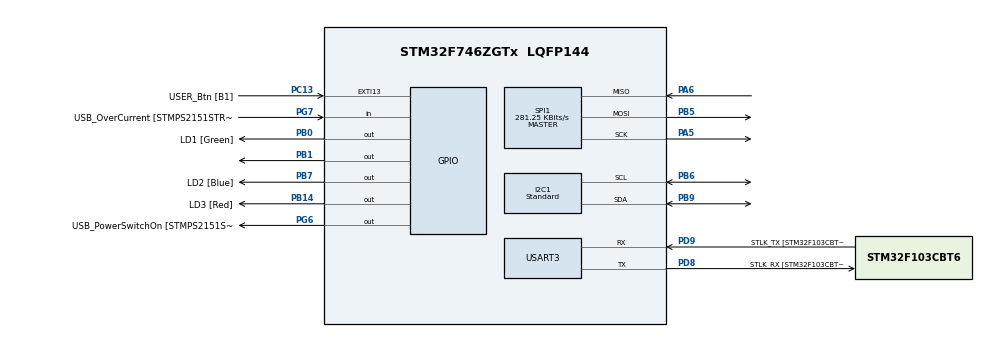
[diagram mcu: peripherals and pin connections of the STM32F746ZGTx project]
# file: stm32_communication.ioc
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FATFS._MAX_SS=1024
FATFS._MIN_SS=512
FREERTOS.Tasks01=defaultTask,24,128,StartDefaultTask,Default,NULL,Dynamic,NULL,NULL
FREERTOS.configUSE_NEWLIB_REENTRANT=1
I2C1.I2C_Speed_Mode=I2C_Standard
I2C1.Timing=0x00808CD2
Mcu.Family=STM32F7
Mcu.Name=STM32F746ZGTx
Mcu.Package=LQFP144
NVIC.I2C1_EV_IRQn=true\:5\:0\:false\:false\:true\:true\:true\:true\:true
NVIC.PriorityGroup=NVIC_PRIORITYGROUP_4
NVIC.SPI1_IRQn=true\:5\:0\:false\:false\:true\:true\:true\:true\:true
NVIC.TIM3_IRQn=true\:15\:0\:false\:false\:true\:false\:false\:true\:true
NVIC.TimeBase=TIM3_IRQn
NVIC.TimeBaseIP=TIM3
PA1.GPIO_Label=RMII_REF_CLK [LAN8742A-CZ-TR_REFCLK0]
PA1.Signal=ETH_REF_CLK
PA10.GPIO_Label=USB_ID
PA10.Signal=USB_OTG_FS_ID
PA11.GPIO_Label=USB_DM
PA11.Signal=USB_OTG_FS_DM
PA12.GPIO_Label=USB_DP
PA12.Signal=USB_OTG_FS_DP
PA13.GPIO_Label=TMS
PA13.Mode=Serial_Wire
PA13.Signal=SYS_JTMS-SWDIO
PA14.GPIO_Label=TCK
PA14.Mode=Serial_Wire
PA14.Signal=SYS_JTCK-SWCLK
PA2.GPIO_Label=RMII_MDIO [LAN8742A-CZ-TR_MDIO]
PA2.Signal=ETH_MDIO
PA5.Mode=Full_Duplex_Master
PA5.Signal=SPI1_SCK
PA6.Mode=Full_Duplex_Master
PA6.Signal=SPI1_MISO
PA7.GPIO_Label=RMII_CRS_DV [LAN8742A-CZ-TR_CRS_DV]
PA7.Signal=ETH_CRS_DV
PA8.GPIO_Label=USB_SOF [TP1]
PA8.Signal=USB_OTG_FS_SOF
PA9.GPIO_Label=USB_VBUS
PA9.Signal=USB_OTG_FS_VBUS
PB0.GPIO_Label=LD1 [Green]
PB0.Signal=GPIO_Output
PB1.Signal=GPIO_Output
PB13.GPIO_Label=RMII_TXD1 [LAN8742A-CZ-TR_TXD1]
PB13.Signal=ETH_TXD1
PB14.GPIO_Label=LD3 [Red]
PB14.Signal=GPIO_Output
PB3.GPIO_Label=SW0
PB3.Signal=SYS_JTDO-SWO
PB5.Mode=Full_Duplex_Master
PB5.Signal=SPI1_MOSI
PB6.GPIO_Pu=GPIO_PULLUP
PB6.Mode=I2C
PB6.Signal=I2C1_SCL
PB7.GPIO_Label=LD2 [Blue]
PB7.Signal=GPIO_Output
PB9.GPIO_Pu=GPIO_PULLUP
PB9.Mode=I2C
PB9.Signal=I2C1_SDA
PC1.GPIO_Label=RMII_MDC [LAN8742A-CZ-TR_MDC]
PC1.Signal=ETH_MDC
PC13.GPIO_Label=USER_Btn [B1]
PC13.Signal=GPXTI13
PC14/OSC32_IN.Mode=LSE-External-Oscillator
PC14/OSC32_IN.Signal=RCC_OSC32_IN
PC15/OSC32_OUT.Mode=LSE-External-Oscillator
PC15/OSC32_OUT.Signal=RCC_OSC32_OUT
PC4.GPIO_Label=RMII_RXD0 [LAN8742A-CZ-TR_RXD0]
PC4.Signal=ETH_RXD0
PC5.GPIO_Label=RMII_RXD1 [LAN8742A-CZ-TR_RXD1]
PC5.Signal=ETH_RXD1
PD8.GPIO_Label=STLK_RX [STM32F103CBT6_PA3]
PD8.Mode=Asynchronous
PD8.Signal=USART3_TX
PD9.GPIO_Label=STLK_TX [STM32F103CBT6_PA2]
PD9.Mode=Asynchronous
PD9.Signal=USART3_RX
PG11.GPIO_Label=RMII_TX_EN [LAN8742A-CZ-TR_TXEN]
PG11.Signal=ETH_TX_EN
PG13.GPIO_Label=RMII_TXD0 [LAN8742A-CZ-TR_TXD0]
PG13.Signal=ETH_TXD0
PG6.GPIO_Label=USB_PowerSwitchOn [STMPS2151STR_EN]
PG6.Signal=GPIO_Output
PG7.GPIO_Label=USB_OverCurrent [STMPS2151STR_FAULT]
PG7.Signal=GPIO_Input
PH0/OSC_IN.GPIO_Label=MCO [STM32F103CBT6_PA8]
PH0/OSC_IN.Mode=HSE-External-Clock-Source
PH0/OSC_IN.Signal=RCC_OSC_IN
PH1/OSC_OUT.Mode=HSE-External-Clock-Source
PH1/OSC_OUT.Signal=RCC_OSC_OUT
ProjectManager.HeapSize=0x200
ProjectManager.StackSize=0x400
ProjectManager.TargetToolchain=STM32CubeIDE
RCC.48MHZClocksFreq_Value=24000000
RCC.AHBFreq_Value=72000000
RCC.APB1CLKDivider=RCC_HCLK_DIV2
RCC.APB1Freq_Value=36000000
RCC.APB1TimFreq_Value=72000000
RCC.APB2Freq_Value=72000000
RCC.APB2TimFreq_Value=72000000
RCC.CortexFreq_Value=72000000
RCC.HCLKFreq_Value=72000000
RCC.HSE_VALUE=8000000
RCC.HSI_VALUE=16000000
RCC.PLLM=4
RCC.PLLMUL=RCC_PLL_MUL9
RCC.PLLN=72
RCC.PLLQ=3
RCC.PLLSourceVirtual=RCC_PLLSOURCE_HSE
RCC.PRESCALERUSB=RCC_USBCLKSOURCE_PLL_DIV1_5
RCC.SYSCLKFreq_VALUE=72000000
RCC.SYSCLKSource=RCC_SYSCLKSOURCE_PLLCLK
RCC.SYSCLKSourceVirtual=RCC_SYSCLKSOURCE_PLLCLK
RCC.USBFreq_Value=48000000
RCC.VCOOutputFreq_Value=144000000
SPI1.BaudRatePrescaler=SPI_BAUDRATEPRESCALER_256
SPI1.CalculateBaudRate=281.25 KBits/s
SPI1.DataSize=SPI_DATASIZE_8BIT
SPI1.Direction=SPI_DIRECTION_2LINES
SPI1.Mode=SPI_MODE_MASTER
SPI1.VirtualType=VM_MASTER
USART3.VirtualMode-Asynchronous=VM_ASYNC
VP_FATFS_VS_Generic.Mode=User_defined
VP_FREERTOS_VS_CMSIS_V2.Mode=CMSIS_V2
VP_SYS_VS_tim3.Mode=TIM3
board=NUCLEO-F746ZG

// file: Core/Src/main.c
/* USER CODE BEGIN Header */
/**
  ******************************************************************************
  * @file           : main.c
  * @brief          : Main program body
  ******************************************************************************
  * @attention
  *
  * Copyright (c) 2023 STMicroelectronics.
  * All rights reserved.
  *
  * This software is licensed under terms that can be found in the LICENSE file
  * in the root directory of this software component.
  * If no LICENSE file comes with this software, it is provided AS-IS.
  *
  ******************************************************************************
  */
/* USER CODE END Header */
#include "main.h"
#include "cmsis_os.h"
#include "fatfs.h"
#include "lwip.h"

/* USER CODE BEGIN Includes */
#include "lib/drivers/I2C/I2C.h"
#include "lib/drivers/SPI/SPI.h"
#include "lib/UL/HTU21D/HTU21D.h"
#include "lib/UL/LCD/display.h"
#include "string.h"
#include "lib/UL/SD/SD.h"
#include "FreeRTOS.h"
#include "queue.h"
#include "task.h"
//#include "message_buffer.h"
/* USER CODE END Includes */

/* USER CODE BEGIN PD */
#define SD_CS_GPIO_Port GPIOB
#define SD_CS_Pin GPIO_PIN_2
/* USER CODE END PD */

I2C_HandleTypeDef hi2c1;

SPI_HandleTypeDef hspi1;

UART_HandleTypeDef huart3;

/* Definitions for defaultTask */
osThreadId_t defaultTaskHandle;
const osThreadAttr_t defaultTask_attributes = {
  .name = "defaultTask",
  .stack_size = 128 * 4,
  .priority = (osPriority_t) osPriorityNormal,
};
/* USER CODE BEGIN PV */

/* Definitions for task */
xTaskHandle display_taskHandle;
xTaskHandle SD_taskHandle;
xTaskHandle HTU_taskHandle;
xTaskHandle ethernet_taskHandle;

i2c_t obj_i2c =
{
  .i2c_handler = &hi2c1,
  .i2c_type    = I2C1,
};

spi_t obj_spi =
{
  .obj_spi_handler = &hspi1,
  .obj_spi_type    = SPI1,
};

extern struct netif gnetif;
/* USER CODE END PV */

void SystemClock_Config(void);
static void MX_GPIO_Init(void);
static void MX_USART3_UART_Init(void);
static void MX_I2C1_Init(void);
static void MX_SPI1_Init(void);
void StartDefaultTask(void *argument);

/* USER CODE BEGIN PFP */
void display_task_entry(void *pvParameters);
void SD_task_entry(void *pvParameters);
void HTU_task_entry(void *pvParameters);
void ethernet_task_entry(void *pvParameters);
QueueHandle_t obj_display_que;

/* USER CODE END PFP */

/* USER CODE BEGIN 0 */

FATFS fs;  // file system
FIL fil; // File
FILINFO fno;
FRESULT fresult;  // result
UINT br, bw;  // File read/write count

/**** capacity related *****/
FATFS *pfs;
DWORD fre_clust;
uint32_t total, free_space;

#define BUFFER_SIZE 128
char buffer[BUFFER_SIZE];  // to store strings..

int i=0;

int bufsize (char *buf)
{
  int i = 0;
  while (*buf++ != '\0')
    i++;
  return i;
}

void clear_buffer (void)
{
  for (int i = 0; i < BUFFER_SIZE; i++)
    buffer[i] = '\0';
}

volatile uint8_t u8_fat_fs_cnt = 0;
volatile uint16_t u16_timer1, u16_timer2;

void SDTimer_Handler(void)
{
  if(u16_timer1 > 0)
    u16_timer1--;

  if(u16_timer2 > 0)
    u16_timer2--;
}

/* USER CODE END 0 */

int main(void)
{

  /* MCU Configuration--------------------------------------------------------*/

  /* Reset of all peripherals, Initializes the Flash interface and the Systick. */
  HAL_Init();

  /* Configure the system clock */
  SystemClock_Config();

  /* Initialize all configured peripherals */
  MX_GPIO_Init();
  MX_USART3_UART_Init();
  MX_I2C1_Init();
  MX_SPI1_Init();
  MX_FATFS_Init();
  /* USER CODE BEGIN 2 */

  i2c_init(&obj_i2c);
  SPI_init(&obj_spi);
//  display_write_test();
//_____________________________________

  HAL_Delay (500);

  /* USER CODE END 2 */

  /* Init scheduler */
  osKernelInitialize();

  /* USER CODE BEGIN RTOS_QUEUES */
  obj_display_que = xQueueCreate(200, sizeof(uint8_t));
  /* USER CODE END RTOS_QUEUES */

  /* Create the thread(s) */
  /* creation of defaultTask */
  defaultTaskHandle = osThreadNew(StartDefaultTask, NULL, &defaultTask_attributes);

  /* USER CODE BEGIN RTOS_THREADS */
  /* add threads, ... */
  xTaskCreate(display_task_entry, "display_task", 128 * 4, NULL, 32 | portPRIVILEGE_BIT, &display_taskHandle);
  xTaskCreate(SD_task_entry, "SD_task", 2 *128 * 4, NULL, 34 | portPRIVILEGE_BIT, &SD_taskHandle);
  xTaskCreate(HTU_task_entry, "HTU_task", 128 * 4, NULL, 33 | portPRIVILEGE_BIT, &HTU_taskHandle);
  xTaskCreate(ethernet_task_entry, "ethernet_task", 128 * 4, NULL, 31 | portPRIVILEGE_BIT, &ethernet_taskHandle);

  /* USER CODE END RTOS_THREADS */

  /* Start scheduler */
  osKernelStart();

  /* We should never get here as control is now taken by the scheduler */
  /* Infinite loop */
  /* USER CODE BEGIN WHILE */
  while (1)
  {

//    HTU21D_handler(&obj_i2c);
//    HAL_Delay(100);
      ethernetif_input(&gnetif);
      sys_check_timeouts();
//    display_run(&obj_i2c);
    /* USER CODE END WHILE */

  }
}

void SystemClock_Config(void)
{
  RCC_OscInitTypeDef RCC_OscInitStruct = {0};
  RCC_ClkInitTypeDef RCC_ClkInitStruct = {0};

  /** Configure LSE Drive Capability
  */
  HAL_PWR_EnableBkUpAccess();

  /** Configure the main internal regulator output voltage
  */
  __HAL_RCC_PWR_CLK_ENABLE();
  __HAL_PWR_VOLTAGESCALING_CONFIG(PWR_REGULATOR_VOLTAGE_SCALE1);

  /** Initializes the RCC Oscillators according to the specified parameters
  * in the RCC_OscInitTypeDef structure.
  */
  RCC_OscInitStruct.OscillatorType = RCC_OSCILLATORTYPE_HSE;
  RCC_OscInitStruct.HSEState = RCC_HSE_ON;
  RCC_OscInitStruct.PLL.PLLState = RCC_PLL_ON;
  RCC_OscInitStruct.PLL.PLLSource = RCC_PLLSOURCE_HSE;
  RCC_OscInitStruct.PLL.PLLM = 4;
  RCC_OscInitStruct.PLL.PLLN = 216;
  RCC_OscInitStruct.PLL.PLLP = RCC_PLLP_DIV2;
  RCC_OscInitStruct.PLL.PLLQ = 3;
  if (HAL_RCC_OscConfig(&RCC_OscInitStruct) != HAL_OK)
  {
    Error_Handler();
  }

  /** Activate the Over-Drive mode
  */
  if (HAL_PWREx_EnableOverDrive() != HAL_OK)
  {
    Error_Handler();
  }

  /** Initializes the CPU, AHB and APB buses clocks
  */
  RCC_ClkInitStruct.ClockType = RCC_CLOCKTYPE_HCLK|RCC_CLOCKTYPE_SYSCLK
                              |RCC_CLOCKTYPE_PCLK1|RCC_CLOCKTYPE_PCLK2;
  RCC_ClkInitStruct.SYSCLKSource = RCC_SYSCLKSOURCE_PLLCLK;
  RCC_ClkInitStruct.AHBCLKDivider = RCC_SYSCLK_DIV1;
  RCC_ClkInitStruct.APB1CLKDivider = RCC_HCLK_DIV4;
  RCC_ClkInitStruct.APB2CLKDivider = RCC_HCLK_DIV2;

  if (HAL_RCC_ClockConfig(&RCC_ClkInitStruct, FLASH_LATENCY_7) != HAL_OK)
  {
    Error_Handler();
  }
}

static void MX_I2C1_Init(void)
{

  hi2c1.Instance = I2C1;
  hi2c1.Init.Timing = 0x20404768;
  hi2c1.Init.OwnAddress1 = 0;
  hi2c1.Init.AddressingMode = I2C_ADDRESSINGMODE_7BIT;
  hi2c1.Init.DualAddressMode = I2C_DUALADDRESS_DISABLE;
  hi2c1.Init.OwnAddress2 = 0;
  hi2c1.Init.OwnAddress2Masks = I2C_OA2_NOMASK;
  hi2c1.Init.GeneralCallMode = I2C_GENERALCALL_DISABLE;
  hi2c1.Init.NoStretchMode = I2C_NOSTRETCH_DISABLE;
  if (HAL_I2C_Init(&hi2c1) != HAL_OK)
  {
    Error_Handler();
  }

  /** Configure Analogue filter
  */
  if (HAL_I2CEx_ConfigAnalogFilter(&hi2c1, I2C_ANALOGFILTER_ENABLE) != HAL_OK)
  {
    Error_Handler();
  }

  /** Configure Digital filter
  */
  if (HAL_I2CEx_ConfigDigitalFilter(&hi2c1, 0) != HAL_OK)
  {
    Error_Handler();
  }

}

static void MX_SPI1_Init(void)
{

  /* SPI1 parameter configuration*/
  hspi1.Instance = SPI1;
  hspi1.Init.Mode = SPI_MODE_MASTER;
  hspi1.Init.Direction = SPI_DIRECTION_2LINES;
  hspi1.Init.DataSize = SPI_DATASIZE_8BIT;
  hspi1.Init.CLKPolarity = SPI_POLARITY_LOW;
  hspi1.Init.CLKPhase = SPI_PHASE_1EDGE;
  hspi1.Init.NSS = SPI_NSS_SOFT;
  hspi1.Init.BaudRatePrescaler = SPI_BAUDRATEPRESCALER_256;
  hspi1.Init.FirstBit = SPI_FIRSTBIT_MSB;
  hspi1.Init.TIMode = SPI_TIMODE_DISABLE;
  hspi1.Init.CRCCalculation = SPI_CRCCALCULATION_DISABLE;
  hspi1.Init.CRCPolynomial = 7;
  hspi1.Init.CRCLength = SPI_CRC_LENGTH_DATASIZE;
  hspi1.Init.NSSPMode = SPI_NSS_PULSE_ENABLE;
  if (HAL_SPI_Init(&hspi1) != HAL_OK)
  {
    Error_Handler();
  }

}

static void MX_USART3_UART_Init(void)
{

  huart3.Instance = USART3;
  huart3.Init.BaudRate = 115200;
  huart3.Init.WordLength = UART_WORDLENGTH_8B;
  huart3.Init.StopBits = UART_STOPBITS_1;
  huart3.Init.Parity = UART_PARITY_NONE;
  huart3.Init.Mode = UART_MODE_TX_RX;
  huart3.Init.HwFlowCtl = UART_HWCONTROL_NONE;
  huart3.Init.OverSampling = UART_OVERSAMPLING_16;
  huart3.Init.OneBitSampling = UART_ONE_BIT_SAMPLE_DISABLE;
  huart3.AdvancedInit.AdvFeatureInit = UART_ADVFEATURE_NO_INIT;
  if (HAL_UART_Init(&huart3) != HAL_OK)
  {
    Error_Handler();
  }

}

static void MX_GPIO_Init(void)
{
  GPIO_InitTypeDef GPIO_InitStruct = {0};

  /* GPIO Ports Clock Enable */
  __HAL_RCC_GPIOC_CLK_ENABLE();
  __HAL_RCC_GPIOH_CLK_ENABLE();
  __HAL_RCC_GPIOA_CLK_ENABLE();
  __HAL_RCC_GPIOB_CLK_ENABLE();
  __HAL_RCC_GPIOD_CLK_ENABLE();
  __HAL_RCC_GPIOG_CLK_ENABLE();

  /*Configure GPIO pin Output Level */
  HAL_GPIO_WritePin(GPIOB, GPIO_PIN_2|LD3_Pin|LD2_Pin, GPIO_PIN_RESET);

  /*Configure GPIO pin Output Level */
  HAL_GPIO_WritePin(USB_PowerSwitchOn_GPIO_Port, USB_PowerSwitchOn_Pin, GPIO_PIN_RESET);

  /*Configure GPIO pin : USER_Btn_Pin */
  GPIO_InitStruct.Pin = USER_Btn_Pin;
  GPIO_InitStruct.Mode = GPIO_MODE_IT_RISING;
  GPIO_InitStruct.Pull = GPIO_NOPULL;
  HAL_GPIO_Init(USER_Btn_GPIO_Port, &GPIO_InitStruct);

  /*Configure GPIO pins : PB2 LD3_Pin LD2_Pin */
  GPIO_InitStruct.Pin = GPIO_PIN_2|LD3_Pin|LD2_Pin;
  GPIO_InitStruct.Mode = GPIO_MODE_OUTPUT_PP;
  GPIO_InitStruct.Pull = GPIO_NOPULL;
  GPIO_InitStruct.Speed = GPIO_SPEED_FREQ_LOW;
  HAL_GPIO_Init(GPIOB, &GPIO_InitStruct);

  /*Configure GPIO pin : USB_PowerSwitchOn_Pin */
  GPIO_InitStruct.Pin = USB_PowerSwitchOn_Pin;
  GPIO_InitStruct.Mode = GPIO_MODE_OUTPUT_PP;
  GPIO_InitStruct.Pull = GPIO_NOPULL;
  GPIO_InitStruct.Speed = GPIO_SPEED_FREQ_LOW;
  HAL_GPIO_Init(USB_PowerSwitchOn_GPIO_Port, &GPIO_InitStruct);

  /*Configure GPIO pin : USB_OverCurrent_Pin */
  GPIO_InitStruct.Pin = USB_OverCurrent_Pin;
  GPIO_InitStruct.Mode = GPIO_MODE_INPUT;
  GPIO_InitStruct.Pull = GPIO_NOPULL;
  HAL_GPIO_Init(USB_OverCurrent_GPIO_Port, &GPIO_InitStruct);

  /*Configure GPIO pins : USB_SOF_Pin USB_ID_Pin USB_DM_Pin USB_DP_Pin */
  GPIO_InitStruct.Pin = USB_SOF_Pin|USB_ID_Pin|USB_DM_Pin|USB_DP_Pin;
  GPIO_InitStruct.Mode = GPIO_MODE_AF_PP;
  GPIO_InitStruct.Pull = GPIO_NOPULL;
  GPIO_InitStruct.Speed = GPIO_SPEED_FREQ_VERY_HIGH;
  GPIO_InitStruct.Alternate = GPIO_AF10_OTG_FS;
  HAL_GPIO_Init(GPIOA, &GPIO_InitStruct);

  /*Configure GPIO pin : USB_VBUS_Pin */
  GPIO_InitStruct.Pin = USB_VBUS_Pin;
  GPIO_InitStruct.Mode = GPIO_MODE_INPUT;
  GPIO_InitStruct.Pull = GPIO_NOPULL;
  HAL_GPIO_Init(USB_VBUS_GPIO_Port, &GPIO_InitStruct);

}

/* USER CODE BEGIN 4 */

/**
 * @brief Function implementing the display_task thread.
 * @param argument: Not used
 * @retval None
 */
/* USER CODE END Header_button_task_entry */
void display_task_entry(void *pvParameters)
{
    volatile uint8_t display_period_ms = 52;
    /* Infinite loop */
    for (;;)
    {
//      ethernetif_input(&gnetif);
//      sys_check_timeouts();
      display_run(&obj_i2c);
      vTaskDelay(display_period_ms);
    }

    vTaskDelay(0);
}

/**
 * @brief Function implementing the ethernet thread.
 * @param argument: Not used
 * @retval None
 */
/* USER CODE END Header_button_task_entry */
void ethernet_task_entry(void *pvParameters)
{
    volatile uint8_t display_period_ms = 10;
    /* Infinite loop */
    for (;;)
    {
      ethernetif_input(&gnetif);
      sys_check_timeouts();
      vTaskDelay(display_period_ms);
    }

    vTaskDelay(0);
}

/**
 * @brief Function implementing the SD_task thread.
 * @param argument: Not used
 * @retval None
 */
/* USER CODE END Header_button_task_entry */
void SD_task_entry(void *pvParameters)
{
    volatile uint32_t SD_period_ms = 60500;

    vTaskDelay(SD_period_ms);
    /* Infinite loop */
    for (;;)
    {
      sd_write();
      vTaskDelay(SD_period_ms);
    }

    vTaskDelay(0);
}

/**
 * @brief Function implementing the HTU_task thread.
 * @param argument: Not used
 * @retval None
 */
/* USER CODE END Header_button_task_entry */
void HTU_task_entry(void *pvParameters)
{
    volatile uint32_t HTU_period_ms = 15000;
    display_init(&obj_display_que);
    vTaskDelay(HTU_period_ms);
    /* Infinite loop */
    for (;;)
    {
      HTU21D_handler(&obj_i2c);
      vTaskDelay(HTU_period_ms);
    }

    vTaskDelay(0);
}

/* USER CODE END 4 */

void StartDefaultTask(void *argument)
{
  /* init code for LWIP */
  MX_LWIP_Init();
  for(;;)
  {
    osDelay(1);
  }
}

void HAL_TIM_PeriodElapsedCallback(TIM_HandleTypeDef *htim)
{
  /* USER CODE BEGIN Callback 0 */
  u8_fat_fs_cnt++;
  if(u8_fat_fs_cnt >= 10)
  {
    u8_fat_fs_cnt = 0;
    SDTimer_Handler();
  }
  /* USER CODE END Callback 0 */
  if (htim->Instance == TIM3) {
    HAL_IncTick();
  }
}

void Error_Handler(void)
{
  __disable_irq();
  while (1)
  {
  }
}
